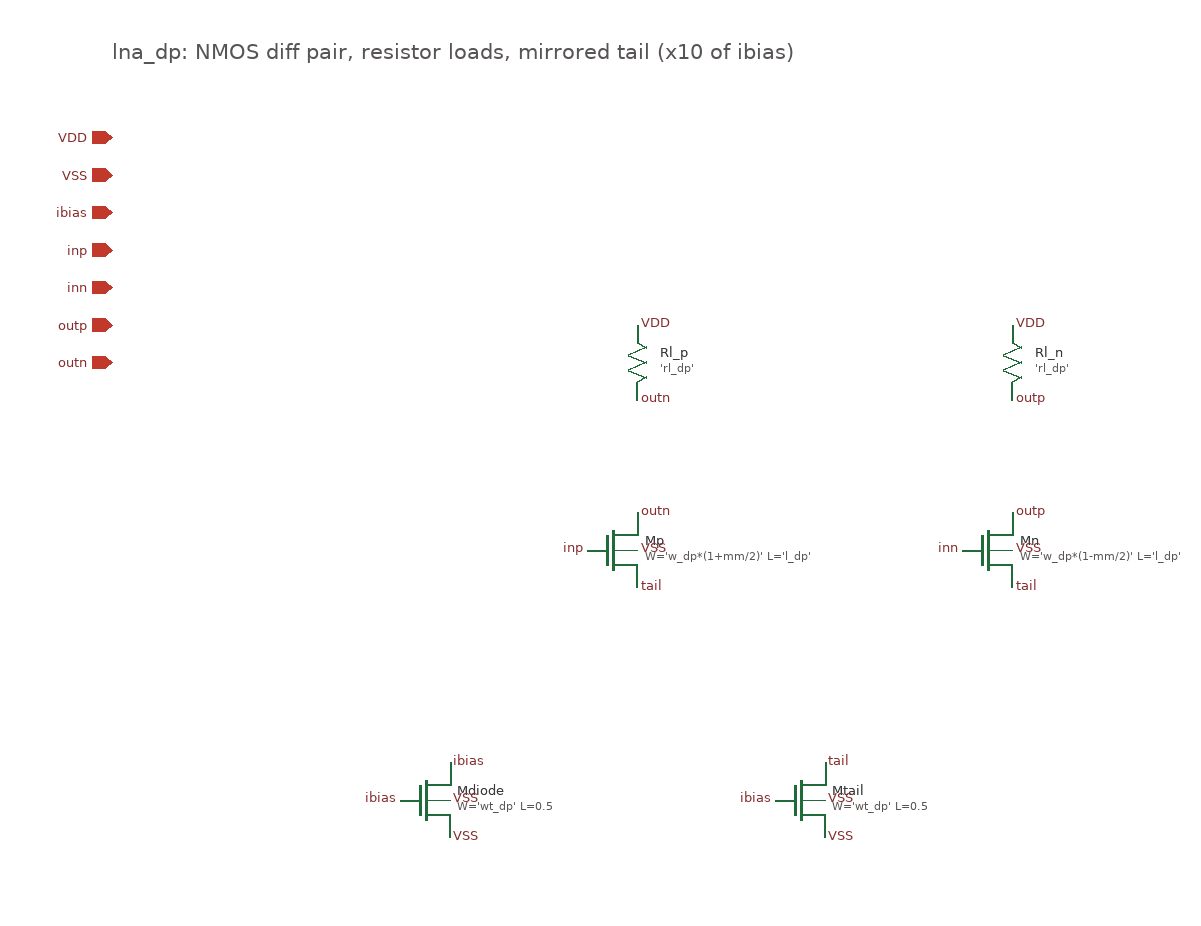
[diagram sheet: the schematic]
v {xschem version=3.4.5 file_version=1.2
}
G {}
K {}
V {}
S {}
E {}
T {lna_dp: NMOS diff pair, resistor loads, mirrored tail (x10 of ibias)} -400 -560 0 0 0.5 0.5 {}
C {devices/iopin.sym} -400 -480 0 0 {name=p1
lab=VDD}
C {devices/iopin.sym} -400 -450 0 0 {name=p2
lab=VSS}
C {devices/iopin.sym} -400 -420 0 0 {name=p3
lab=ibias}
C {devices/iopin.sym} -400 -390 0 0 {name=p4
lab=inp}
C {devices/iopin.sym} -400 -360 0 0 {name=p5
lab=inn}
C {devices/iopin.sym} -400 -330 0 0 {name=p6
lab=outp}
C {devices/iopin.sym} -400 -300 0 0 {name=p7
lab=outn}
C {devices/res.sym} 20 -300 0 0 {name=Rl_p
value='rl_dp'
m=1}
C {devices/lab_pin.sym} 20 -330 0 1 {name=p8
sig_type=std_logic
lab=VDD}
C {devices/lab_pin.sym} 20 -270 0 1 {name=p9
sig_type=std_logic
lab=outn}
C {sky130_fd_pr/nfet_01v8.sym} 0 -150 0 0 {name=Mp
nf=4
mult=1
ad="'int((nf+1)/2) * W/nf * 0.29'"
pd="'2*int((nf+1)/2) * (W/nf + 0.29)'"
as="'int((nf+2)/2) * W/nf * 0.29'"
ps="'2*int((nf+2)/2) * (W/nf + 0.29)'"
nrd="'0.29 / W'"
nrs="'0.29 / W'"
sa=0
sb=0
sd=0
L='l_dp'
W='w_dp*(1+mm/2)'
model=nfet_01v8
spiceprefix=X}
C {devices/lab_pin.sym} 20 -180 0 1 {name=p10
sig_type=std_logic
lab=outn}
C {devices/lab_pin.sym} -20 -150 0 0 {name=p11
sig_type=std_logic
lab=inp}
C {devices/lab_pin.sym} 20 -120 0 1 {name=p12
sig_type=std_logic
lab=tail}
C {devices/lab_pin.sym} 20 -150 0 1 {name=p13
sig_type=std_logic
lab=VSS}
C {devices/res.sym} 320 -300 0 0 {name=Rl_n
value='rl_dp'
m=1}
C {devices/lab_pin.sym} 320 -330 0 1 {name=p14
sig_type=std_logic
lab=VDD}
C {devices/lab_pin.sym} 320 -270 0 1 {name=p15
sig_type=std_logic
lab=outp}
C {sky130_fd_pr/nfet_01v8.sym} 300 -150 0 0 {name=Mn
nf=4
mult=1
ad="'int((nf+1)/2) * W/nf * 0.29'"
pd="'2*int((nf+1)/2) * (W/nf + 0.29)'"
as="'int((nf+2)/2) * W/nf * 0.29'"
ps="'2*int((nf+2)/2) * (W/nf + 0.29)'"
nrd="'0.29 / W'"
nrs="'0.29 / W'"
sa=0
sb=0
sd=0
L='l_dp'
W='w_dp*(1-mm/2)'
model=nfet_01v8
spiceprefix=X}
C {devices/lab_pin.sym} 320 -180 0 1 {name=p16
sig_type=std_logic
lab=outp}
C {devices/lab_pin.sym} 280 -150 0 0 {name=p17
sig_type=std_logic
lab=inn}
C {devices/lab_pin.sym} 320 -120 0 1 {name=p18
sig_type=std_logic
lab=tail}
C {devices/lab_pin.sym} 320 -150 0 1 {name=p19
sig_type=std_logic
lab=VSS}
C {sky130_fd_pr/nfet_01v8.sym} 150 50 0 0 {name=Mtail
nf=2
mult=10
ad="'int((nf+1)/2) * W/nf * 0.29'"
pd="'2*int((nf+1)/2) * (W/nf + 0.29)'"
as="'int((nf+2)/2) * W/nf * 0.29'"
ps="'2*int((nf+2)/2) * (W/nf + 0.29)'"
nrd="'0.29 / W'"
nrs="'0.29 / W'"
sa=0
sb=0
sd=0
L=0.5
W='wt_dp'
model=nfet_01v8
spiceprefix=X}
C {devices/lab_pin.sym} 170 20 0 1 {name=p20
sig_type=std_logic
lab=tail}
C {devices/lab_pin.sym} 130 50 0 0 {name=p21
sig_type=std_logic
lab=ibias}
C {devices/lab_pin.sym} 170 80 0 1 {name=p22
sig_type=std_logic
lab=VSS}
C {devices/lab_pin.sym} 170 50 0 1 {name=p23
sig_type=std_logic
lab=VSS}
C {sky130_fd_pr/nfet_01v8.sym} -150 50 0 0 {name=Mdiode
nf=2
mult=1
ad="'int((nf+1)/2) * W/nf * 0.29'"
pd="'2*int((nf+1)/2) * (W/nf + 0.29)'"
as="'int((nf+2)/2) * W/nf * 0.29'"
ps="'2*int((nf+2)/2) * (W/nf + 0.29)'"
nrd="'0.29 / W'"
nrs="'0.29 / W'"
sa=0
sb=0
sd=0
L=0.5
W='wt_dp'
model=nfet_01v8
spiceprefix=X}
C {devices/lab_pin.sym} -130 20 0 1 {name=p24
sig_type=std_logic
lab=ibias}
C {devices/lab_pin.sym} -170 50 0 0 {name=p25
sig_type=std_logic
lab=ibias}
C {devices/lab_pin.sym} -130 80 0 1 {name=p26
sig_type=std_logic
lab=VSS}
C {devices/lab_pin.sym} -130 50 0 1 {name=p27
sig_type=std_logic
lab=VSS}
